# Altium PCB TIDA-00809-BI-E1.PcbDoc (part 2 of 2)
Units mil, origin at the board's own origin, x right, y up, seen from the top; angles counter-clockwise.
Board outline 5150 x 1000 mil, 2 copper layers (Top Layer, Bottom Layer), stack 62 mil thick; 167 components, 75 nets, 346 pads, 70 vias.

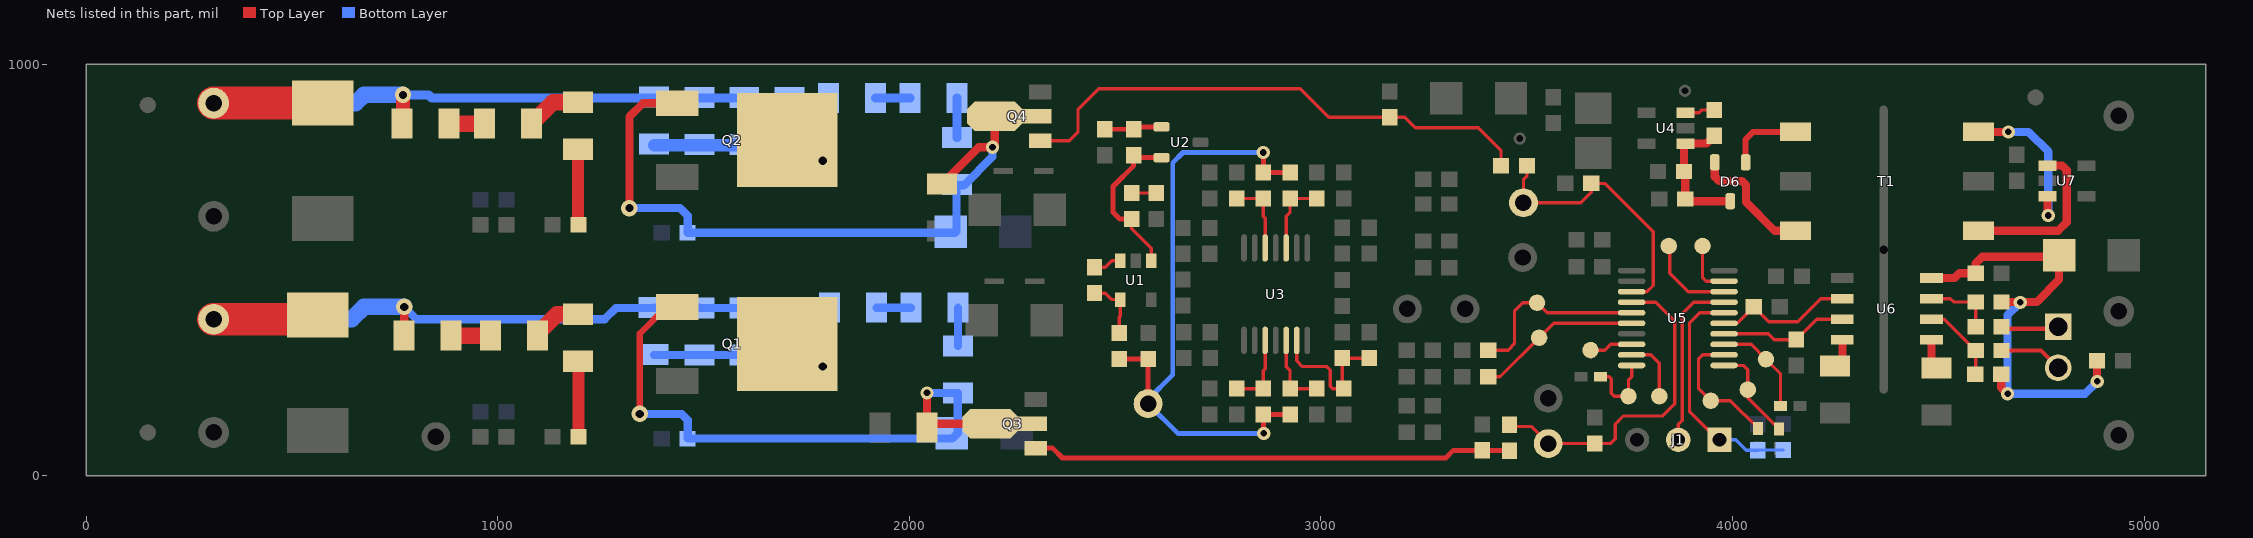
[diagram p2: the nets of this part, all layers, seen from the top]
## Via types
v1: diameter 32, hole 16, Top Layer to Bottom Layer, tented both sides, 59 vias
v2: diameter 40, hole 20, Top Layer to Bottom Layer, tented both sides, 11 vias

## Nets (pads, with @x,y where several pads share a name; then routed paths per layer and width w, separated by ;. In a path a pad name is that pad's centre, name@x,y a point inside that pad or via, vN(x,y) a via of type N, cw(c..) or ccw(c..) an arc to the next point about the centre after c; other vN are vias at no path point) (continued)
NetC7_2: C7.2 R32.2 R34.2 U3.13 | length 355
  Top Layer w8: U3.13@2941.18,328.78 2941.18,278.82 2955,265 3014.43,265 3022.7,256.73 3022.7,217.3 3028.5,211.5 R34.2@3055,211.5 3052,214.5 R32.2@3052,285.5 C7.2@3117,285.5
NetC21_1: C21.1 J1.1 R60.1 U5.16 | length 585.2
  Top Layer w8: J1.1@3973,78 3966,85 3895.5,155.5 3895.5,371.5 3919.8,395.8 U5.16@3979.2,395.8
  Bottom Layer w8: J1.1@3968,87 4008,87 4033.31,61.69 C21.1@4061.3,61.69 4062.11,62.5 R60.1@4123,62.5
NetC22_2: C22.2 D8.1 Q2.G Q4.2 Q4.4 R12.2 R62.2 | length 1688.1
  Top Layer w20: v2(1320,650) 1320,872.13 1352.64,904.76 Q2.G@1436.14,904.76 ; R12.2@2079,708.09 2168.91,798 v1(2202,798) 2207.57,803.57 Q4.4@2207.57,873
  Bottom Layer w12: D8.1@2114.51,593 D8.1@2116,594.49
  Bottom Layer w20: v2(1320,650) 1443,650 1461.5,631.5 C22.2@1461.5,590 2111.51,590 2114.51,593 2114.51,705.42 2132.42,705.42 2202,775 v1(2202,798)
NetC23_2: C23.2 D7.1 Q1.G Q3.2 Q3.4 R11.2 R61.1 | length 1591.1
  Top Layer w15: v2(1345,150) 1345,345 1409.76,409.76 Q1.G@1436.14,409.76
  Top Layer w20: v1(2043,201) 2043.09,200.91 R11.2@2043.09,117 2052.09,126 Q3.4@2196.57,126 ; Q3.4@2170,135 Q3.4@2204.57,135
  Bottom Layer w20: v2(1345,150) 1447,150 1461.5,135.5 C23.2@1461.5,90 2104.53,90 2117.53,103 R61.1@2117.53,200.44 ; v1(2043,201) 2116.98,201 R61.1@2117.53,200.44 ; R61.1@2118,200.91 R61.1@2117.53,200.44
NetD1_2: D1.2 R1.1 R66.1 R67.2 R70.2 R71.2 R73.2 TP1.1 | length 1850.3
  Top Layer w22: R1.1@767.91,855 R1.1@770,857.09 ; R1.1@772.91,860 R1.1@777.91,855
  Top Layer w35: R1.1@770,857.09 v2(770,925)
  Top Layer w80: TP1.1@310,905 574.51,905 D1.2@575,905.49
  Bottom Layer w22: v2(770,925) 832.09,925 840,917.09 1707,917.09 R67.2@1709,919.09 1801.83,919.09 R66.1@1803.91,917
  Bottom Layer w40: TP1.1@310,905 655,905 675,925 v2(770,925)
NetD2_2: D2.2 R2.1 R65.1 R68.2 R69.2 R72.2 R74.2 TP3.1 | length 1979.1
  Top Layer w20: R2.1@772.91,340 v2(772.91,410)
  Top Layer w80: TP3.1@310,380 574.51,380 D2.2@575,380.49
  Bottom Layer w20: v2(772.91,410) 802.91,380 1260,380 1287.09,407.09 R72.2@1490,407.09 ; R74.2@1379,408.09 1489,408.09 R72.2@1490,407.09 ; R65.1@1805.91,408 1805.83,408.09 R68.2@1709,408.09 1708,407.09 R69.2@1600,407.09 R72.2@1490,407.09
  Bottom Layer w40: TP3.1@310,380 645,380 675,410 v2(772.91,410)
NetD6_1: D6.1 T1.4 | length 184
  Top Layer w15: D6.1@4031.72,761.27 4031.72,817 4049.72,835 T1.4@4152.5,835
NetD6_2: D6.2 T1.6 | length 308.9
  Top Layer w20: D6.2@3956.91,761.27 3956.91,726.43 3967.32,716.02 4022.32,716.02 4032.32,706.02 4032.32,665.02 4102.34,595 T1.6@4152.5,595
NetJ1_2: J1.2 U5.17 | length 430.1
  Top Layer w8: J1.2@3868,87 3868,124.5 3877.5,134 3877.5,393.5 3905.39,421.39 U5.17@3979.2,421.39 ; J1.2@3873,78 J1.2@3877.5,82.5
NetL1_2: L1.2 U6.4 | length 71.3
  Top Layer w20: L1.2@4249,266.09 4266.73,283.82 U6.4@4266.73,330
NetL2_1: L2.1 U6.5 | length 73.8
  Top Layer w20: U6.5@4483.27,330 4483.27,272.82 L2.1@4495,261.09
NetQ1_D: Q1.D R68.1 R69.1 R72.1 R74.1 | length 421.6
  Bottom Layer w20: R74.1@1380,292.91 R72.1@1490,292.91 R69.1@1600,292.91 1710,292.91 1762.09,292.91 v2(1790,265)
NetQ2_D: Q2.D R67.1 R70.1 R71.1 R73.1 | length 532.6
  Top Layer w30: Q2.D@1703.86,815 1753.86,765 v2(1790,765)
  Bottom Layer w30: R73.1@1380,802.91 1490,802.91 1600,802.91 1710,802.91 1747.91,765 v2(1790,765)
NetQ3_1: Q3.1 R42.2 R44.2 | length 1169.2
  Top Layer w12: Q3.1@2306.8,66.94 2348.06,66.94 2372.03,42.97 3302.97,42.97 3321.5,61.5 R42.2@3392,61.5 3457,61.5 R44.2@3458,60.5
NetQ4_1: Q4.1 R35.2 R43.2 | length 1303
  Top Layer w8: Q4.1@2317.8,813.94 2388.94,813.94 2410,835 2410,890 2460,940 2950,940 3019.5,870.5 R35.2@3167,870.5 3204,870.5 3229.5,845 3382,845 3437.5,789.5 R43.2@3437.5,753
NetR1_2: R1.2 R5.1 | length 85.8
  Top Layer w40: R1.2@882.09,855 R5.1@967.91,855
NetR2_2: R2.2 R6.1 | length 95.8
  Top Layer w40: R2.2@887.09,340 R6.1@982.91,340
NetR5_2: R5.2 R9.1 | length 134.5
  Top Layer w40: R5.2@1082.09,855 1134.17,907.09 R9.1@1195,907.09
NetR6_2: R6.2 R10.1 | length 117.4
  Top Layer w40: R6.2@1097.09,345 1144.17,392.09 R10.1@1195,392.09
NetR7_1: R7.1 R9.2 | length 183.5
  Top Layer w30: R9.2@1195,792.91 1195,611.5 R7.1@1196.5,610
NetR8_1: R8.1 R10.2 | length 183.5
  Top Layer w30: R10.2@1195,277.91 1196.5,276.42 R8.1@1196.5,95
NetR13_1: R13.1 U1.3 | length 69.1
  Top Layer w8: R13.1@2450,506.5 2476.5,506.5 2492.24,522.24 U1.3@2512.6,522.24
NetR13_2: R13.2 R15.1 U1.4 | length 151.5
  Top Layer w8: R13.2@2450,443.5 2476.5,443.5 2492.24,427.76 U1.4@2512.6,427.76 2512.6,387.6 2510,385 R15.1@2510,346.5
NetR14_2: R14.2 R17.1 U2.1 | length 140.2
  Top Layer w12: R14.2@2475,841.5 R17.1@2545,841.5 2550.91,847.4 U2.1@2612.76,847.4
NetR16_1: R16.1 R17.2 U1.1 U2.2 | length 402.1
  Top Layer w8: R16.1@2540,623.5 2540,600 2587.4,552.6 U1.1@2587.4,522.24
  Top Layer w12: R16.1@2540,623.5 2511.5,623.5 2495,640 2495,702.51 2545,752.51 R17.2@2545,778.5 2550.91,772.6 U2.2@2612.76,772.6
NetR16_2: R16.2 R18.2 | length 60
  Top Layer w8: R16.2@2540,686.5 R18.2@2600,686.5
NetR23_2: R23.2 R25.2 U3.10 | length 184.1
  Top Layer w8: R23.2@2795,211.5 R25.2@2860,211.5 2860,255 2864.41,259.41 U3.10@2864.41,328.78
NetR24_2: R24.2 R26.2 U3.5 | length 187.1
  Top Layer w8: R24.2@2795,673.5 R26.2@2860,673.5 2860,630 2864.41,625.59 U3.5@2864.41,553.19
NetR27_2: R27.2 R30.2 U3.12 | length 186.2
  Top Layer w8: U3.12@2915.59,328.78 2915.59,264.41 2925,255 R27.2@2925,211.5 R30.2@2990,211.5
NetR28_2: R28.2 R29.1 U3.3 | length 189.2
  Top Layer w8: U3.3@2915.59,553.19 2915.59,630.59 2925,640 R28.2@2925,673.5 R29.1@2990,673.5
NetR40_2: R40.2 TP12.1 U5.5 | length 452.8
  Top Layer w8: R40.2@3406.5,305 3455,305 3470,320 3470,400 3490,420 TP12.1@3525,420 3549.2,395.8 U5.5@3754.8,395.8
NetR41_2: R41.2 TP13.1 U5.6 | length 402.2
  Top Layer w8: R41.2@3406.5,240 3435,240 TP13.1@3530,335 3565.2,370.2 U5.6@3754.8,370.2
NetR46_2: R46.2 TP17.1 U5.10 | length 186.6
  Top Layer w8: R46.2@3678.62,240 3700,240 3705,235 3705,200 3712,193 TP17.1@3747,193 3747,232 3754.8,239.8 U5.10@3754.8,267.84 ; U5.10@3747,267.84 U5.10@3747,268
NetR48_1: R48.1 U4.3 | length 72.7
  Top Layer w8: U4.3@3885.56,881.43 3918.52,881.43 3925.61,888.52 R48.1@3955.32,888.52
NetR50_2: R50.2 TP22.1 U5.12 | length 330.1
  Top Layer w8: TP22.1@3947,182 TP22.1@3951.85,182 ; U5.12@3979.2,293.43 3927.43,293.43 3917,283 3917,212 3941,188 3945.85,188 TP22.1@3951.85,182 ; R50.2@4062,114.62 3994.62,182 TP22.1@3951.85,182 ; R50.2@4062.31,114.93 R50.2@4064,113.24
NetR51_2: R51.2 TP24.1 U5.13 | length 245.4
  Top Layer w8: U5.13@3979.2,319.02 4044.98,319.02 TP24.1@4081,283 4116.38,247.62 R51.2@4116.38,169
NetR53_2: R53.2 TP23.1 U5.11 | length 237.5
  Top Layer w8: U5.11@3979.2,267.84 4026.16,267.84 4037,257 TP23.1@4037,209 4037,189.24 R53.2@4113,113.24
NetR54_1: R54.1 R55.1 U6.7 | length 172.4
  Top Layer w8: U6.7@4483.27,430 4529,430 4537,422 R54.1@4590.5,422 ; R55.1@4590.5,362 R54.1@4590.5,422 ; R54.1@4590.5,423.82 R54.1@4590.5,422
NetR56_1: R56.1 R57.1 U6.6 | length 197.2
  Top Layer w8: U6.6@4483.27,380 4514.5,380 4556.82,337.69 4556.82,337.5 4565.02,329.3 4565.2,329.3 R56.1@4590.5,304 4590.5,247 R57.1@4589.5,246
NetR61_2: R61.2 R63.1 | length 92.9
  Bottom Layer w20: R61.2@2118,315.09 2118.09,315.17 R63.1@2118.09,408
NetR62_1: R62.1 R64.2 | length 95.9
  Bottom Layer w22: R62.1@2116,821.09 2116.09,821.17 R64.2@2116.09,917
NetR63_2: R63.2 R65.2 | length 83.8
  Bottom Layer w20: R65.2@1920.09,408 R63.2@2003.91,408
NetR64_1: R64.1 R66.2 | length 83.8
  Bottom Layer w22: R66.2@1918.09,917 R64.1@2001.91,917
NetT1_1: T1.1 U7.1 | length 416.4
  Top Layer w20: T1.1@4608.5,584 T1.1@4597.5,595 4791,595 4812,616 4812,741.83 4800.43,753.4 U7.1@4765,753.4
NetT1_3: T1.3 U7.3 | length 391.8
  Top Layer w20: T1.3@4597.5,835 v1(4670,835) ; U7.3@4765,678.6 4765,634 v1(4767,632)
  Bottom Layer w20: v1(4670,835) 4719,835 4767,787 v1(4767,632)
NetTP16_1: TP16.1 U5.8 | length 105.6
  Top Layer w8: TP16.1@3655,305 3690,305 3704.02,319.02 U5.8@3754.8,319.02
NetTP18_1: TP18.1 U5.9 | length 155.7
  Top Layer w8: U5.9@3754.8,293.43 3801.57,293.43 3822,273 TP18.1@3822,193
NetTP19_1: TP19.1 U5.18 | length 216.9
  Top Layer w8: TP19.1@3847,558 3847,491.98 3892,446.98 U5.18@3979.2,446.98
NetTP21_1: TP21.1 U5.19 | length 132.7
  Top Layer w8: TP21.1@3927,558 3927,481 3935.43,472.57 U5.19@3979.2,472.57
PWM_0: R43.1 R45.1 TP11.1 U5.3 | length 678.8
  Top Layer w8: R43.1@3500.5,753 3500.5,727.5 3492,719 TP11.1@3492,663 3631.5,663 3656.5,688 R45.1@3656.5,710 3690,710 3807,593 3807,461.98 3792,446.98 U5.3@3754.8,446.98
PWM_1: R44.1 R47.1 TP15.1 U5.4 | length 804.9
  Top Layer w8: R44.1@3457,119.5 3510.5,119.5 TP15.1@3552,78 3703,78 3715,90 3715,125 3735,145 3830,145 3859.5,174.5 3859.5,375.5 3813.61,421.39 U5.4@3754.8,421.39
SCL: R52.1 U5.14 U6.3 | length 327.7
  Top Layer w8: U5.14@3979.2,344.61 4087,344.61 4101.12,330.5 R52.1@4155,330.5 4204.5,380 U6.3@4266.73,380 U6.3@4280.51,380
SCL_ISO: J2.2 R56.2 | length 154.9
  Top Layer w10: R56.2@4653.5,304 4749,304 J2.2@4791,262
SDA: R49.1 U5.15 U6.2 | length 355.9
  Top Layer w8: U5.15@3979.2,370.2 4011.71,370.2 R49.1@4051.5,410 4087.5,374 4158,374 4214,430 U6.2@4266.73,430 U6.2@4280.51,430
SDA_ISO: J2.1 R55.2 | length 140.1
  Top Layer w10: R55.2@4653,357 4786,357 J2.1@4791,362
VCC_0: C16.1 C17.1 D6.3 R48.2 U4.1 | length 326.7
  Top Layer w20: R48.2@3955.32,825.53 3936.41,806.62 U4.1@3885.56,806.62 3881.81,802.88 C16.1@3881.81,739.02 3884.81,736.02 C17.1@3884.81,672.02 3890.06,666.78 D6.3@3994.32,666.78
VCC_ISO: C19.1 D9.1 R54.2 R57.2 R58.1 U6.8 | length 1150.4
  Top Layer w20: U6.8@4469.49,480 U6.8@4483.27,480 4539,480 4551,492 C19.1@4590.5,492 4590.5,515.89 4606.62,532 4790.26,532 D9.1@4793.26,535 4793.26,476.26 4739,422 R54.2@4653.5,422 ; R57.2@4652.5,246 4652.5,214.5 v1(4668,199) ; R58.1@4885.5,279 4885.5,229.5 v1(4886,229)
  Bottom Layer w20: v1(4699,421) 4668,390 v1(4668,199) 4856,199 v1(4886,229)
VREF_PH: C1.2 R15.2 R25.1 R26.1 R27.1 R28.1 TP6.1 | length 1553.3
  Top Layer w12: R15.2@2510,283.5 C1.2@2580,283.5 TP6.1@2580,175 ; R25.1@2860,148.5 2860,103.63 v1(2860.92,102.71) ; v1(2860,785) R26.1@2860,736.5 R28.1@2925,736.5 ; R25.1@2860.92,148.5 R27.1@2925,148.5
  Bottom Layer w12: v1(2860,785) 2665,785 2640,760 2640,245 2580,185 TP6.1@2580,175 2652.29,102.71 v1(2860.92,102.71)
pads on no net: FID1.1 FID2.1 FID3.1 FID4.1 FID5.1 FID6.1 U4.4

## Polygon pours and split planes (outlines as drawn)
GND on Bottom Layer "Multi-Layer-No Net" (solid, remove dead copper, pour order 9): 2405,950 2430,975 2470,975 4170,975 4187,958 4187,523 4198,512 4285,512 4294,503 4294,43 4281,30 4205,30 4195,30 2440,30 2405,65 2405,945

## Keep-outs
Keep-Out Layer:
  pour cut-out: 4190,977 4190,540 4320,540 4320,27 4440,27 4440,540 4565,540 4565,977
  lines w3.94: 50,25 5117,25 5117,983 50,983 50,25
  text ".Layer_Name" at 297,-1308.49 h60

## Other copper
Top Layer:
  text ".Layer_Name" at 297,-1308.49 h60
Bottom Layer:
  text ".Layer_Name" at 297,-1308.49 h60

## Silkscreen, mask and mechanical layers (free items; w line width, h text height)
Top Overlay:
  drawing of 208 lines, arcs and shapes, not listed
  text "GND" at 3842,967 h35
  text "GND_ISO" at 5058,786 h50 r90
  text "PWM_0" at 3445,590 h30
  text "A" at 2152,543 h35
  text "K" at 2377,543 h35
  text "CH-1" at 365,520 h35
  text "CH-2" at 365,460 h35
  text "B" at 1970,370 h35
  text "+3.3V" at 5039,341 h50 r90
  text "A" at 2146,276 h35
  text "K" at 2363,258 h35
  text "B" at 3875,155 h35
  text "GND" at 785,65 h35 r90
  text "GND_ISO" at 5037,11 h50 r90
  text "PWM_1" at 3620,10 h30
  text ".Layer_Name" at 297,-1308.49 h60
Bottom Overlay:
  lines w20: 5,500 2274,500 ; 2635,35 2635,236 2626,245 2564,307 2345,307 2345,500 2580,500 2580,720 2640,720 2640,970
  text "K" at 2019,639 h35 r180
  text "A" at 2334,576 h35
  text "TIDA-00809-BI" at 1301,410 h60
  text "REV :" at 1198,303 h60
  text ".PCB_Rev" at 894,299 h60
  text "K" at 2026,158 h35 r180
  text "A" at 2324,87 h35
  text ".Layer_Name" at 297,-1308.49 h60
Top Paste:
  text ".Layer_Name" at 297,-1308.49 h60
Bottom Paste:
  text ".Layer_Name" at 297,-1308.49 h60
Top Solder:
  text ".Layer_Name" at 297,-1308.49 h60
  text ".Layer_Name" at 297,-1308.49 h60
Bottom Solder:
  text ".Layer_Name" at 297,-1308.49 h60
Drill Guide:
  text ".Layer_Name" at 297,-1308.49 h60
M1 Board Outline:
  the board outline again, w10
M2 Board Dimensions:
  rectangle: 314.5,-455 689.5,-330
  rectangle: 189.5,-330 314.5,-205
  lines w7: 189.5,-330 1189.5,-330 ; 314.5,-455 314.5,-205 ; 439.5,-455 439.5,-205 ; 689.5,-455 689.5,-205 ; 939.5,-455 939.5,-205 ; 189.5,-455 189.5,-205 1189.5,-205 1189.5,-455 189.5,-455
  lines w10: 189.5,-520 189.5,-500 ; 249.5,-530 189.5,-510 ; 249.5,-490 189.5,-510 ; 413.58,-510 189.5,-510 ; 965.42,-510 1189.5,-510 ; 1129.5,-530 1189.5,-510 ; 1129.5,-490 1189.5,-510 ; 1189.5,-520 1189.5,-500
  text "1000 (mil)" at 423.58,-545.99 h60
M3 3D STEP Top:
  text ".Layer_Name" at 297,-1308.49 h60
M4 3D STEP Bottom:
  text ".Layer_Name" at 297,-1308.49 h60
M5 Assembly Top:
  circle w6: c3820,810 r7.07
  circle w6: c2652.93,845 r7.07
  circle w6: c2587.93,490 r7.07
  circle w6: c4585,595 r20.23
  circle w6: c4741,752 r7.07
  circle w6: c1381,411 r12
  circle w6: c1389,906 r12
  circle w6: c2268.64,810 r13.36
  circle w6: c2269,66 r12
  circle w6: c3968.92,85 r6.08
  circle w6: c3997.73,805 r5.1
  lines w3.94: 2094,473 2107,473 ; 2100,490 2107,483 ; 2112,455 2107,460 2107,483 ; 2116,473.5 2132.5,473.5 ; 2136.5,492 2141.5,487 2141.5,464 ; 2138,740 2151,740 ; 2144,757 2151,750 ; 2148.5,457 2141.5,464 ; 2154.5,474 2141.5,474 ; 2156,722 2151,727 2151,750 ; 2160,740.5 2176.5,740.5 ; 2180.5,759 2185.5,754 2185.5,731 ; 2192.5,724 2185.5,731 ; 2198.5,741 2185.5,741 ; 2107,473 2116,464 2116,483 2116,482 2107,473 ; 2107,473 2107,483 ; 2141.5,464 2141.5,474 ; 2141.5,474 2132.5,465 2132.5,464 2132.5,483 2141.5,474 ; 2151,740 2151,750 ; 2151,740 2160,749 2160,750 2160,731 2151,740 ; 2185.5,731 2185.5,741 ; 2185.5,741 2176.5,750 2176.5,731 2176.5,732 2185.5,741
  lines w6: 4790.54,366.54 ccw(c4787,363) 4792,363
  lines w10: -572,-1380.17 6028,-1380.17 ; -572,-1176.83 6030,-1176.83 ; -572,-973.5 -572,-1583.5 3433,-1583.5 6030,-1583.5 6030,-973.5 -571.5,-973.5 -571.5,-1583.5 1004,-1583.5 ; 1893,-1583.5 1893,-973.5 ; 3160,-1176.83 3160,-973.5 ; 4000,-1176.83 4000,-973.5 ; 4622,-1590 4622,-1387.17
  text "K" at 3512,827 h25
  text "A" at 3270,825 h25
  text "K" at 4749,605 h25
  text "A" at 4955,605 h25
  text "A" at 2155,552 h25
  text "K" at 2386,550 h25
  text "K" at 2413,360 h25
  text "A" at 2108,354 h25
  text "COMPONENTS MARKED 'DNP' SHOULD NOT BE POPULATED." at 873.5,-768.5 h25
  text "ASSEMBLY VARIANT:" at 873,-884 h25
  text ".VariantName" at 1909,-884 h25
  text "PCB VIEWED FROM TOP SIDE" at -508.5,-1105.67 h25
  text "BOARD #:" at 1968,-1105.67 h25
  text ".PRJ_Number" at 2513.5,-1105.67 h25
  text "REV:" at 3358,-1105.67 h25
  text ".PCB_Rev" at 3649.5,-1105.67 h25
  text "SVN REV:" at 4196,-1105.67 h25
  text ".VersionControl_RevNumber" at 4702,-1105.67 h25
  text "LAYER NAME =" at -319,-1290 h30
  text ".Layer_Name" at 230,-1293 h25
  text "IGNORE ->" at 3592,-1294 h25
  text "TID #:" at 1996,-1311.67 h30
  text ".tiD" at 2198.5,-1312.67 h30
  text "PLOT NAME =" at -508.5,-1514.34 h25
  text ".plot_File_Name" at 297,-1514.34 h25
  text "GENERATED    :" at 1970,-1514.34 h25
  text ".Print_Date" at 2839.5,-1514.34 h25
  text ".Print_Time" at 3568.5,-1514.34 h25
  text "TEXAS INSTRUMENTS" at 4833,-1514.34 h25
M6 Assembly Bottom:
  lines w10: -572.5,-1177.33 6029.5,-1177.33 ; -570.5,-1380.67 6029.5,-1380.67 ; 835.5,-1590.5 835.5,-1387.67 ; 1457.5,-1177.33 1457.5,-974 ; 2297.5,-1177.33 2297.5,-974 ; 3564.5,-1584 3564.5,-974 ; 4453.5,-1584 6029,-1584 6029,-974 -572.5,-974 -572.5,-1584 2024.5,-1584 6029.5,-1584 6029.5,-974
  text "K" at 2021,606 h25 r180
  text "A" at 2307,577 h25
  text "K" at 2023,121 h25 r180
  text "A" at 2310,90 h25
  text "COMPONENTS MARKED 'DNP' SHOULD NOT BE POPULATED." at 5822,-768 h25
  text ".VariantName" at 4778,-884 h25
  text "ASSEMBLY VARIANT:" at 5817,-884 h25
  text ".VersionControl_RevNumber" at 755.5,-1106.17 h25
  text "SVN REV:" at 1261.5,-1106.17 h25
  text ".PCB_Rev" at 1808,-1106.17 h25
  text "REV:" at 2099.5,-1106.17 h25
  text ".PRJ_Number" at 2944,-1106.17 h25
  text "BOARD #:" at 3489.5,-1106.17 h25
  text "PCB VIEWED FROM BOTTOM SIDE" at 5966,-1106.17 h25
  text "IGNORE ->" at 1845,-1288 h25
  text "TID #:" at 3519,-1295.67 h30
  text ".PRJ_Number" at 3275.5,-1301.67 h30
  text ".Layer_Name" at 5464,-1302 h30
  text "LAYER NAME =" at 5931,-1306 h30
  text "TEXAS INSTRUMENTS" at 624.5,-1514.84 h25
  text ".Print_Time" at 1889,-1514.84 h25
  text ".Print_Date" at 2618,-1514.84 h25
  text "GENERATED    :" at 3487.5,-1514.84 h25
  text ".plot_File_Name" at 5160.5,-1514.84 h25
  text "PLOT NAME =" at 5966,-1514.84 h25
M9 Title Sheet:
  drawing of 57 lines, arcs and shapes, not listed
  text "1" at 459.84,7586.5 h70
  text "2" at 2955.5,7586.5 h70
  text "3" at 5444.84,7586.5 h70
  text "4" at 7951.51,7586.5 h70
  text "5" at 10450.5,7586.5 h70
  text "6" at 12955.5,7586.5 h70
  text "A" at -696.5,6443.5 h70
  text "A" at 14103.5,6443.5 h70
  text "B" at -696.5,4063.5 h70
  text "B" at 14103.5,4063.5 h70
  text "C" at -696.5,1688.5 h70
  text "C" at 14103.5,1688.5 h70
  text "PROJECT TITLE:" at 11063.5,-172.5 h45
  text ".PRJ_Title" at 11113.5,-305.83 h70
  text "DESIGNED FOR:" at 11063.5,-473.5 h45
  text ".PRJ_Customer" at 11113.5,-613.5 h70
  text "D" at -696.5,-681.5 h70
  text "D" at 14103.5,-681.5 h70
  text "FILE NAME:" at 11063.5,-773.5 h45
  text ".PCB_File_Name_No_Path" at 11113.5,-893.5 h70
  text "Texas Instruments (TI) and/or its licensors do not warrant the accuracy or completeness of this specification" at 6094,-1055.34 h45
  text "ENGINEER:" at 11063.5,-1063.5 h45
  text "LAYOUT BY:" at 12568.5,-1063.5 h45
  text "or any information contained therein. TI and/or its licensors do not warrant that this design will meet" at 6049.01,-1168 h45
  text ".PRJ_Engineer" at 11113.5,-1218.49 h70
  text ".PCB_Layout" at 12619,-1218.49 h70
  text "the specifications, will be suitable for your application or fit for any particular purpose, or will operate in" at 6049.01,-1280.67 h45
  text "ALTIUM DESIGNER VERSION:" at 12568.5,-1373.5 h45
  text "an implementation. TI and/or its licensors do not warrant that the design is production worthy. You should" at 6049.01,-1393.33 h45
  text "completely validate and test your design implementation to confirm the system functionality for your application." at 6094,-1506 h45
  text ".print_Scale" at 11113.5,-1506.83 h70
  text ".Application_BuildNumber" at 12619,-1506.83 h70
  text "1" at 459.84,-1713.5 h70
  text "2" at 2955.5,-1713.5 h70
  text "3" at 5444.84,-1713.5 h70
  text "4" at 7951.51,-1713.5 h70
  text "5" at 10450.5,-1713.5 h70
  text "6" at 12955.5,-1713.5 h70
M10 Fab Notes:
  drawing of 228 lines, arcs and shapes, not listed
  text "DESIGN INFORMATION" at 12101.02,6360 h60
  text "(REFER ALSO ARRAY/PANEL PROFILING INFORMATION)" at 11739.46,6198.29 h60
  text "BOARD SIZE" at 11053.46,6194 h60
  text "5150MIL" at 11515.78,6066.18 h60
  text "X" at 12021.46,6066.18 h60
  text "1000MIL" at 12252.78,6066.18 h60
  text "Number of Layers :" at 11456.46,5869 h60
  text "2" at 12551.27,5859 h60
  text "MIN. TRACK WIDTH:" at 11456.46,5730 h60
  text "8" at 12552.7,5730 h60
  text "MIL" at 12707.46,5730 h60
  text "MIN. CLEARANCE:" at 11456.46,5598 h60
  text "MIL" at 12707.46,5598 h60
  text "8" at 12545,5597 h60
  text "MIN. VIA PAD SIZE:" at 11456.46,5466 h60
  text "30" at 12522.71,5466 h60
  text "MIL" at 12707.46,5466 h60
  text "0.177mm (7MIL)" at 12151.46,5324.29 h60
  text "MINIMUM ANNULAR RING" at 11127.23,5320 h60
  text "EXTERNAL" at 12859.46,5320 h60
  text "PER" at 11327.23,5202 h60
  text "IPC-D-275 CLASS 2 LEVEL C" at 11547.23,5202 h60
  text "MIL, HOLES" at 13035.46,5089.71 h60
  text "+/-" at 12643,5089 h60
  text "+/-" at 13497,5089 h60
  text "REGISTRATION TOLERANCES:" at 11127.23,5084 h60
  text "METAL" at 12327,5084 h60
  text "5" at 12903.2,5084 h60
  text "3" at 13736.2,5084 h60
  text "MIL" at 13852.46,5084 h60
  text "MATERIAL:" at 11052.46,4874.54 h60
  text "FR4" at 13475,4740 h60
  text "FR-4 High Tg" at 12038.9,4734.21 h60
  text "FR-408" at 11473.46,4725.64 h60
  text "X" at 12774.46,4726 h60
  text "OTHER" at 12961.46,4725.64 h60
  text "63 MIL (1.6mm) +/-10%" at 11793.56,4562.92 h60
  text "THICKNESS:" at 11127.23,4558.64 h60
  text "X" at 11665.4,4558.64 h60
  text "OTHER" at 13078.46,4558.64 h60
  text "TOLERANCE:" at 11127.23,4400.64 h60
  text "X" at 11966.53,4400.64 h60
  text "ANSI IPC-6012 TYPE 3 CLASS 2" at 12153.48,4400.64 h60
  text "OTHER +/-" at 12153.46,4244.64 h60
  text "BOW & TWIST:" at 11127.23,4087.64 h60
  text "X" at 11966.53,4087.64 h60
  text "ANSI IPC-6012 TYPE 3 CLASS 2" at 12153.48,4087.64 h60
  text "OTHER +/-" at 12153.46,3929.13 h60
  text "COPPER THICKNESS (FINISHED):" at 11052.46,3793.64 h60
  text "1.4MIL (1oz)" at 11932.46,3640.92 h60
  text "2MIL (1.4oz)" at 12699.46,3640.92 h60
  text "2.8MIL (2oz)" at 13426.46,3640.92 h60
  text "OUTER:" at 11409.46,3636.64 h60
  text "X" at 11804,3636 h60
  text "1.4MIL (1oz)" at 11932.46,3483.92 h60
  text "2.8MIL (2oz)" at 12699.46,3483.92 h60
  text "N/A" at 13426,3484.29 h60
  text "INNER SIGNAL:" at 11120.38,3479.64 h60
  text "DRILLING:" at 11052.46,3340.64 h60
  text "REFERENCE:" at 11127.23,3223.64 h60
  text "X" at 11775.46,3223.64 h60
  text "AS SHOWN" at 11962.46,3223.64 h60
  text "X" at 12676.46,3223.64 h60
  text "NC_DRILL FILES" at 12813.46,3223.64 h60
  text "PTH MIN COPPER THICKNESS:" at 11127.23,3065.64 h60
  text "X" at 12477.46,3065.64 h60
  text "1MIL" at 12614.46,3065.64 h60
  text "OTHER" at 13111.46,3065.64 h60
  text "BOARD FINISH:" at 11052.46,2906.64 h60
  text "SILKSCREEN:" at 11207.68,2788.64 h60
  text "X" at 12156.46,2788.64 h60
  text "TOP" at 12282.46,2788.64 h60
  text "X" at 12666.46,2788.64 h60
  text "BOTTOM" at 12793.46,2788.64 h60
  text "SILKSCREEN COLOR:" at 11207.68,2621.64 h60
  text "X" at 12155.42,2621.64 h60
  text "WHITE" at 12282.46,2621.64 h60
  text "OTHER" at 12793.46,2621.64 h60
  text "SOLDER RESIST COLOR:" at 11207.68,2451.64 h60
  text "X" at 11775.42,2292.44 h60
  text "GREEN" at 11902.46,2292.44 h60
  text "BLUE" at 12493.46,2292.44 h60
  text "OTHER" at 13031.46,2292.44 h60
  text "IMMERSION GOLD (ENIG)" at 12113.46,2103.92 h60
  text "ENEPIG" at 13451,2100.64 h60
  text "SURFACE FINISH:" at 11052.46,2099.64 h60
  text "X" at 11926.51,2099.64 h60
  text "IMM. TIN/SILVER OR EQUIV" at 11382,1942.64 h60
  text "OTHER" at 12813.46,1942.64 h60
  text "ARRAY/PANEL:" at 11052.46,1763.64 h60
  text "CUT AND TRIM PER MECH LAYER 1" at 12113.46,1759.35 h60
  text "N.C. ROUTE" at 12113.46,1607.64 h60
  text "X" at 12792.46,1607.64 h60
  text "V. SCORE" at 12979.46,1607.64 h60
  text "CERTIFICATION:" at 11052.46,1470.64 h60
  text "MATERIALS AND WORKMANSHIP FOR ALL PCBS" at 11777.46,1470.64 h60
  text "TO MEET OR EXCEED THE REQUIREMENTS OF:" at 11777.46,1372.64 h60
  text "X" at 11403.96,1236.13 h60
  text "ANSI IPC-A-600F CLASS ->" at 11542.96,1236.13 h60
  text "X" at 13182.02,1236.13 h60
  text "2" at 13300.96,1236.14 h60
  text "1" at 12985.96,1234.64 h60
  text "3" at 13654.96,1234.64 h60
  text "X" at 11406.02,1076.64 h60
  text "UL 94V-0" at 11542.96,1076.64 h60
  text "X" at 12218.02,1076.64 h60
  text "RoHS" at 12354.96,1076.64 h60
  text "OTHER" at 12999.36,1076.64 h60
  text "PER ORDER" at 13396.42,1076.64 h60
  text "VIA TENTING:" at 12270,943 h60
  text "X" at 13036.29,943.11 h60
  text "ADDITIONAL REQUIREMENTS:" at 11052.46,935.64 h60
  text "YES" at 12819.67,933.92 h60
  text "NO" at 13184.47,928.69 h60
  text "MICROSECTION:" at 11127.23,820.64 h60
  text "YES" at 12032.96,820.64 h60
  text "IMPEDANCE CONTROL:" at 12292,814 h60
  text "YES" at 13276,813 h60
  text "X" at 13818,806 h60
  text "NO" at 13651.47,795.69 h60
  text "REQUIRED" at 12894.46,664.49 h60
  text "BARE BOARD ELEC. TEST:" at 11127.23,661.64 h60
  text "NONE" at 12432.96,661.64 h60
  text "X" at 12767.46,661.64 h60
  text "PER ORDER" at 13486.46,661.64 h60
  text "MANUFACTURER'S UL:" at 11127.23,504.64 h60
  text "RAIL" at 12292.96,500.35 h60
  text "METAL" at 12784.77,500.35 h60
  text "X" at 13160,500 h60
  text "SILK" at 13296.46,500.35 h60
M11 Gerber Information:
  lines w10: -572,-1380.17 6028,-1380.17 ; -572,-1176.83 6030,-1176.83 ; -572,-973.5 -572,-1583.5 3433,-1583.5 6030,-1583.5 6030,-973.5 -571.5,-973.5 -571.5,-1583.5 1004,-1583.5 ; 1893,-1583.5 1893,-973.5 ; 3160,-1176.83 3160,-973.5 ; 4000,-1176.83 4000,-973.5 ; 4622,-1590 4622,-1387.17
  text "ALL ARTWORK VIEWED FROM TOP SIDE" at -508.5,-1105.67 h60
  text "BOARD #:" at 1968,-1105.67 h60
  text ".PRJ_Number" at 2513.5,-1105.67 h40
  text "REV:" at 3358,-1105.67 h60
  text ".PCB_Rev" at 3649.5,-1105.67 h60
  text "SVN REV:" at 4196,-1105.67 h60
  text ".VersionControl_RevNumber" at 4702,-1105.67 h60
  text "LAYER NAME =" at -508.5,-1308.49 h60
  text ".tiD" at 2339.5,-1317.67 h40
  text "TID #:" at 1974,-1322.67 h60
  text "PLOT NAME =" at -508.5,-1514.34 h60
  text ".plot_File_Name" at 297,-1514.34 h60
  text "GENERATED    :" at 1970,-1514.34 h60
  text ".Print_Date" at 2839.5,-1514.34 h60
  text ".Print_Time" at 3568.5,-1514.34 h60
  text "TEXAS INSTRUMENTS" at 4833,-1514.34 h60
M12 Stackup:
  lines w6: 11080,7010 13630,7010 ; 11080,7114.4 13630,7114.4 ; 11020,6525 ccw(c11054,6525) 11054,6491 13656,6491 ccw(c13656,6525) 13690,6525 13690,7231 ccw(c13656,7231) 13656,7265 11054,7265 ccw(c11054,7231) 11020,7231 11020,6525
  text "Layer Stack Up Detail for: TIDA-00809-BI-E1" at 11080,7147.1 h57
  text "Layer" at 11080,7075.4 h24
  text "Gerber" at 11975.81,7075.4 h24
  text "Copper" at 12539.33,7075.4 h24
  text "Dielectric" at 13142.04,7075.4 h24
  text "Name" at 11080,7027.4 h24
  text "Document" at 11975.81,7027.4 h24
  text "Thickness" at 12539.33,7027.4 h24
  text "Material" at 13142.04,7027.4 h24
  text "Top Solder Mask" at 11080,6934.44 h34
  text "(.GTS)" at 11975.81,6934.44 h34
  text "Solder Resist" at 13142.04,6934.44 h34
  text "Top Layer" at 11080,6837.69 h34
  text "(.GTL)" at 11975.81,6837.69 h34
  text "1.4mil" at 12539.33,6837.69 h34
  text "FR4" at 13142.04,6789.31 h34
  text "Bottom Layer" at 11080,6740.94 h34
  text "(.GBL)" at 11975.81,6740.94 h34
  text "1.4mil" at 12539.33,6740.94 h34
  text "Bottom Solder Mask" at 11080,6644.19 h34
  text "(.GBS)" at 11975.81,6644.19 h34
  text "Solder Resist" at 13142.04,6644.19 h34
M13 Component Bodies Top:
  text ".Layer_Name" at 297,-1308.49 h60
M14 Component Bodies Bottom:
  text ".Layer_Name" at 297,-1308.49 h60
M15 Courtyards Top:
  text ".Layer_Name" at 297,-1308.49 h60
M16 Courtyards Bottom:
  text ".Layer_Name" at 297,-1308.49 h60
Drill Drawing:
  text ".legend" at 248,2786 h60
  text "Drill Table" at 245,2615 h60
  text "FOR 16MIL DRILL +0/-16MIL" at 259,2495 h60
  text "FOR 20MIL DRILL +0/-20MIL" at 259,2365 h60
  text "FOR PTH DRILL +/-3MIL" at 254,2235 h60
  text "FOR NPTH DRILL +/-2MIL" at 256,2134 h60
  text ".Layer_Name" at 297,-1308.49 h60

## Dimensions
0,0 to 0,1000 on M2 Board Dimensions
0,1000 to 5150,1000 on M2 Board Dimensions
